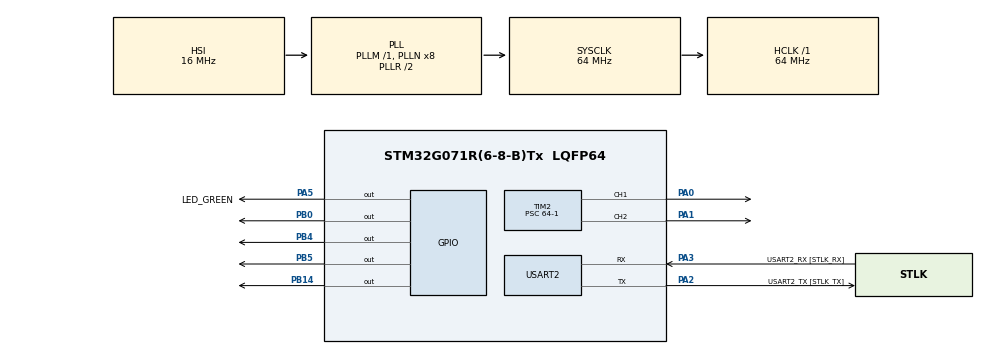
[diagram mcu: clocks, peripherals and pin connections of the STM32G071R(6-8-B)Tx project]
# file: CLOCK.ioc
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Mcu.Family=STM32G0
Mcu.Name=STM32G071R(6-8-B)Tx
Mcu.Package=LQFP64
PA0.Signal=S_TIM2_CH1_ETR
PA1.Signal=S_TIM2_CH2
PA13.GPIO_Label=TMS
PA13.Mode=Serial_Wire
PA13.Signal=SYS_SWDIO
PA14-BOOT0.GPIO_Label=TCK
PA14-BOOT0.Mode=Serial_Wire
PA14-BOOT0.Signal=SYS_SWCLK
PA2.GPIO_Label=USART2_TX [STLK_TX]
PA2.GPIO_PuPd=GPIO_PULLUP
PA2.Mode=Asynchronous
PA2.Signal=USART2_TX
PA3.GPIO_Label=USART2_RX [STLK_RX]
PA3.GPIO_PuPd=GPIO_PULLUP
PA3.Mode=Asynchronous
PA3.Signal=USART2_RX
PA5.GPIO_Label=LED_GREEN
PA5.GPIO_Speed=GPIO_SPEED_FREQ_HIGH
PA5.Signal=GPIO_Output
PB0.Signal=GPIO_Output
PB14.Signal=GPIO_Output
PB4.Signal=GPIO_Output
PB5.Signal=GPIO_Output
PC13.Mode=SYS_WakeUp1
PC13.Signal=SYS_WKUP2
PC14-OSC32_IN\ (PC14).Mode=LSE-External-Oscillator
PC14-OSC32_IN\ (PC14).Signal=RCC_OSC32_IN
PC15-OSC32_OUT\ (PC15).Mode=LSE-External-Oscillator
PC15-OSC32_OUT\ (PC15).Signal=RCC_OSC32_OUT
PF0-OSC_IN\ (PF0).GPIO_Label=MCO
PF0-OSC_IN\ (PF0).Mode=HSE-External-Oscillator
PF0-OSC_IN\ (PF0).Signal=RCC_OSC_IN
PF1-OSC_OUT\ (PF1).Mode=HSE-External-Oscillator
PF1-OSC_OUT\ (PF1).Signal=RCC_OSC_OUT
ProjectManager.HeapSize=0x200
ProjectManager.StackSize=0x400
ProjectManager.TargetToolchain=STM32CubeIDE
RCC.ADCFreq_Value=64000000
RCC.AHBFreq_Value=64000000
RCC.CortexFreq_Value=64000000
RCC.EXTERNAL_CLOCK_VALUE=12288000
RCC.HCLKFreq_Value=64000000
RCC.HSE_VALUE=8000000
RCC.HSI_VALUE=16000000
RCC.SYSCLKFreq_VALUE=64000000
RCC.SYSCLKSource=RCC_SYSCLKSOURCE_PLLCLK
RCC.VCOOutputFreq_Value=128000000
SH.S_TIM2_CH1_ETR.0=TIM2_CH1,PWM Generation1 CH1
SH.S_TIM2_CH2.0=TIM2_CH2,PWM Generation2 CH2
TIM2.AutoReloadPreload=TIM_AUTORELOAD_PRELOAD_ENABLE
TIM2.Channel-PWM\ Generation1\ CH1=TIM_CHANNEL_1
TIM2.Channel-PWM\ Generation2\ CH2=TIM_CHANNEL_2
TIM2.Period=100
TIM2.Prescaler=64-1
USART2.VirtualMode-Asynchronous=VM_ASYNC
VP_TIM2_VS_ClockSourceINT.Mode=Internal
board=NUCLEO-G071RB

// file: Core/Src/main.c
/* USER CODE BEGIN Header */
/**
  ******************************************************************************
  * @file           : main.c
  * @brief          : Main program body
  ******************************************************************************
  * @attention
  *
  * Copyright (c) 2023 STMicroelectronics.
  * All rights reserved.
  *
  * This software is licensed under terms that can be found in the LICENSE file
  * in the root directory of this software component.
  * If no LICENSE file comes with this software, it is provided AS-IS.
  *
  ******************************************************************************
  */
/* USER CODE END Header */
#include "main.h"

#define FORWARD_STATE HAL_GPIO_ReadPin(GPIOA, GPIO_PIN_9)
#define LEFT_STATE HAL_GPIO_ReadPin(GPIOC, GPIO_PIN_7)
#define RIGHT_STATE HAL_GPIO_ReadPin(GPIOA, GPIO_PIN_8)
#define BACKWARD_STATE HAL_GPIO_ReadPin(GPIOA, GPIO_PIN_7)

TIM_HandleTypeDef htim2;

UART_HandleTypeDef huart2;

void SystemClock_Config(void);
static void MX_GPIO_Init(void);
static void MX_USART2_UART_Init(void);
static void MX_TIM2_Init(void);

int main(void)
{
  /* USER CODE BEGIN 1 */
 //int32_t CH1_DC = 0;
  /* USER CODE END 1 */

  /* MCU Configuration--------------------------------------------------------*/

  /* Reset of all peripherals, Initializes the Flash interface and the Systick. */
  HAL_Init();

  /* Configure the system clock */
  SystemClock_Config();

  /* Initialize all configured peripherals */
  MX_GPIO_Init();
  MX_USART2_UART_Init();
  MX_TIM2_Init();
  /* USER CODE BEGIN 2 */
  HAL_TIM_PWM_Start(&htim2, TIM_CHANNEL_1);
  HAL_TIM_PWM_Start(&htim2, TIM_CHANNEL_2);
  void FORWARD_DIR(void)
    {
    	HAL_GPIO_WritePin(GPIOB, GPIO_PIN_0|GPIO_PIN_4,  GPIO_PIN_RESET);
    	HAL_GPIO_WritePin(GPIOB, GPIO_PIN_14|GPIO_PIN_5,  GPIO_PIN_SET);
    	TIM2->CCR1 = 70;
    	TIM2->CCR2 = 70;
    	// GIVE PWMA 100% AND PWMB 100%
    	}

  void BACKWARD_DIR(void)
	{
		HAL_GPIO_WritePin(GPIOB, GPIO_PIN_0|GPIO_PIN_4,  GPIO_PIN_SET);
		HAL_GPIO_WritePin(GPIOB, GPIO_PIN_14|GPIO_PIN_5,  GPIO_PIN_RESET);
		TIM2->CCR1 = 70;
		TIM2->CCR2 = 70;
		// GIVE PWMA 100% AND PWMB 100%
		}

  void LEFT_DIR(void)
    {
    	HAL_GPIO_WritePin(GPIOB, GPIO_PIN_8|GPIO_PIN_4,  GPIO_PIN_RESET);
    	HAL_GPIO_WritePin(GPIOB, GPIO_PIN_14|GPIO_PIN_5,  GPIO_PIN_SET);
    	TIM2->CCR1 = 10;
    	TIM2->CCR2 = 80;
    	// GIVE PWMA AND PWMB
    	}

  void RIGHT_DIR(void)
    {
    	HAL_GPIO_WritePin(GPIOB, GPIO_PIN_8|GPIO_PIN_4,  GPIO_PIN_RESET);
    	HAL_GPIO_WritePin(GPIOB, GPIO_PIN_14|GPIO_PIN_5,  GPIO_PIN_SET);
    	TIM2->CCR1 = 80;
    	TIM2->CCR2 = 10;
    	// GIVE PWMA AND PWMB
    	}

  void STOP(void)
      {
      	HAL_GPIO_WritePin(GPIOB, GPIO_PIN_8|GPIO_PIN_4,  GPIO_PIN_RESET);
      	HAL_GPIO_WritePin(GPIOB, GPIO_PIN_14|GPIO_PIN_5,  GPIO_PIN_RESET);
      	TIM2->CCR1 = 0;
      	TIM2->CCR2 = 0;
      	// GIVE PWMA AND PWMB
      	}

  /* USER CODE END 2 */

  /* Infinite loop */
  while (1)
  {
	  if(FORWARD_STATE == 1)
		  {
			  FORWARD_DIR();
		  }
	  if(LEFT_STATE == 1)
		  {
			  LEFT_DIR();
		  }
	  if(RIGHT_STATE == 1)
		  {
			  RIGHT_DIR();
		  }
	  if(BACKWARD_STATE == 1)
		  {
			  BACKWARD_DIR();
		  }
	  if(FORWARD_STATE == 0 && LEFT_STATE == 0 && RIGHT_STATE == 0 && BACKWARD_STATE == 0)
		  {
		      STOP();
		  }
  }
}

void SystemClock_Config(void)
{
  RCC_OscInitTypeDef RCC_OscInitStruct = {0};
  RCC_ClkInitTypeDef RCC_ClkInitStruct = {0};

  /** Configure the main internal regulator output voltage
  */
  HAL_PWREx_ControlVoltageScaling(PWR_REGULATOR_VOLTAGE_SCALE1);

  /** Initializes the RCC Oscillators according to the specified parameters
  * in the RCC_OscInitTypeDef structure.
  */
  RCC_OscInitStruct.OscillatorType = RCC_OSCILLATORTYPE_HSI;
  RCC_OscInitStruct.HSIState = RCC_HSI_ON;
  RCC_OscInitStruct.HSIDiv = RCC_HSI_DIV1;
  RCC_OscInitStruct.HSICalibrationValue = RCC_HSICALIBRATION_DEFAULT;
  RCC_OscInitStruct.PLL.PLLState = RCC_PLL_ON;
  RCC_OscInitStruct.PLL.PLLSource = RCC_PLLSOURCE_HSI;
  RCC_OscInitStruct.PLL.PLLM = RCC_PLLM_DIV1;
  RCC_OscInitStruct.PLL.PLLN = 8;
  RCC_OscInitStruct.PLL.PLLP = RCC_PLLP_DIV2;
  RCC_OscInitStruct.PLL.PLLQ = RCC_PLLQ_DIV2;
  RCC_OscInitStruct.PLL.PLLR = RCC_PLLR_DIV2;
  if (HAL_RCC_OscConfig(&RCC_OscInitStruct) != HAL_OK)
  {
    Error_Handler();
  }

  /** Initializes the CPU, AHB and APB buses clocks
  */
  RCC_ClkInitStruct.ClockType = RCC_CLOCKTYPE_HCLK|RCC_CLOCKTYPE_SYSCLK
                              |RCC_CLOCKTYPE_PCLK1;
  RCC_ClkInitStruct.SYSCLKSource = RCC_SYSCLKSOURCE_PLLCLK;
  RCC_ClkInitStruct.AHBCLKDivider = RCC_SYSCLK_DIV1;
  RCC_ClkInitStruct.APB1CLKDivider = RCC_HCLK_DIV1;

  if (HAL_RCC_ClockConfig(&RCC_ClkInitStruct, FLASH_LATENCY_2) != HAL_OK)
  {
    Error_Handler();
  }
}

static void MX_TIM2_Init(void)
{

  TIM_ClockConfigTypeDef sClockSourceConfig = {0};
  TIM_MasterConfigTypeDef sMasterConfig = {0};
  TIM_OC_InitTypeDef sConfigOC = {0};

  htim2.Instance = TIM2;
  htim2.Init.Prescaler = 64-1;
  htim2.Init.CounterMode = TIM_COUNTERMODE_UP;
  htim2.Init.Period = 100;
  htim2.Init.ClockDivision = TIM_CLOCKDIVISION_DIV1;
  htim2.Init.AutoReloadPreload = TIM_AUTORELOAD_PRELOAD_ENABLE;
  if (HAL_TIM_Base_Init(&htim2) != HAL_OK)
  {
    Error_Handler();
  }
  sClockSourceConfig.ClockSource = TIM_CLOCKSOURCE_INTERNAL;
  if (HAL_TIM_ConfigClockSource(&htim2, &sClockSourceConfig) != HAL_OK)
  {
    Error_Handler();
  }
  if (HAL_TIM_PWM_Init(&htim2) != HAL_OK)
  {
    Error_Handler();
  }
  sMasterConfig.MasterOutputTrigger = TIM_TRGO_RESET;
  sMasterConfig.MasterSlaveMode = TIM_MASTERSLAVEMODE_DISABLE;
  if (HAL_TIMEx_MasterConfigSynchronization(&htim2, &sMasterConfig) != HAL_OK)
  {
    Error_Handler();
  }
  sConfigOC.OCMode = TIM_OCMODE_PWM1;
  sConfigOC.Pulse = 0;
  sConfigOC.OCPolarity = TIM_OCPOLARITY_HIGH;
  sConfigOC.OCFastMode = TIM_OCFAST_DISABLE;
  if (HAL_TIM_PWM_ConfigChannel(&htim2, &sConfigOC, TIM_CHANNEL_1) != HAL_OK)
  {
    Error_Handler();
  }
  if (HAL_TIM_PWM_ConfigChannel(&htim2, &sConfigOC, TIM_CHANNEL_2) != HAL_OK)
  {
    Error_Handler();
  }
  HAL_TIM_MspPostInit(&htim2);

}

static void MX_USART2_UART_Init(void)
{

  huart2.Instance = USART2;
  huart2.Init.BaudRate = 115200;
  huart2.Init.WordLength = UART_WORDLENGTH_8B;
  huart2.Init.StopBits = UART_STOPBITS_1;
  huart2.Init.Parity = UART_PARITY_NONE;
  huart2.Init.Mode = UART_MODE_TX_RX;
  huart2.Init.HwFlowCtl = UART_HWCONTROL_NONE;
  huart2.Init.OverSampling = UART_OVERSAMPLING_16;
  huart2.Init.OneBitSampling = UART_ONE_BIT_SAMPLE_DISABLE;
  huart2.Init.ClockPrescaler = UART_PRESCALER_DIV1;
  huart2.AdvancedInit.AdvFeatureInit = UART_ADVFEATURE_NO_INIT;
  if (HAL_UART_Init(&huart2) != HAL_OK)
  {
    Error_Handler();
  }
  if (HAL_UARTEx_SetTxFifoThreshold(&huart2, UART_TXFIFO_THRESHOLD_1_8) != HAL_OK)
  {
    Error_Handler();
  }
  if (HAL_UARTEx_SetRxFifoThreshold(&huart2, UART_RXFIFO_THRESHOLD_1_8) != HAL_OK)
  {
    Error_Handler();
  }
  if (HAL_UARTEx_DisableFifoMode(&huart2) != HAL_OK)
  {
    Error_Handler();
  }

}

static void MX_GPIO_Init(void)
{
  GPIO_InitTypeDef GPIO_InitStruct = {0};

  /* GPIO Ports Clock Enable */
  __HAL_RCC_GPIOC_CLK_ENABLE();
  __HAL_RCC_GPIOF_CLK_ENABLE();
  __HAL_RCC_GPIOA_CLK_ENABLE();
  __HAL_RCC_GPIOB_CLK_ENABLE();

  /*Configure GPIO pin Output Level */
  HAL_GPIO_WritePin(LED_GREEN_GPIO_Port, LED_GREEN_Pin, GPIO_PIN_RESET);

  /*Configure GPIO pin Output Level */
  HAL_GPIO_WritePin(GPIOB, GPIO_PIN_0|GPIO_PIN_14|GPIO_PIN_4|GPIO_PIN_5, GPIO_PIN_RESET);

  /*Configure GPIO pin : LED_GREEN_Pin */
  GPIO_InitStruct.Pin = LED_GREEN_Pin;
  GPIO_InitStruct.Mode = GPIO_MODE_OUTPUT_PP;
  GPIO_InitStruct.Pull = GPIO_NOPULL;
  GPIO_InitStruct.Speed = GPIO_SPEED_FREQ_HIGH;
  HAL_GPIO_Init(LED_GREEN_GPIO_Port, &GPIO_InitStruct);

  /*Configure GPIO pins : PA7 PA8 PA9 */
  GPIO_InitStruct.Pin = GPIO_PIN_7|GPIO_PIN_8|GPIO_PIN_9;
  GPIO_InitStruct.Mode = GPIO_MODE_INPUT;
  GPIO_InitStruct.Pull = GPIO_NOPULL;
  HAL_GPIO_Init(GPIOA, &GPIO_InitStruct);

  /*Configure GPIO pins : PB0 PB14 PB4 PB5 */
  GPIO_InitStruct.Pin = GPIO_PIN_0|GPIO_PIN_14|GPIO_PIN_4|GPIO_PIN_5;
  GPIO_InitStruct.Mode = GPIO_MODE_OUTPUT_PP;
  GPIO_InitStruct.Pull = GPIO_NOPULL;
  GPIO_InitStruct.Speed = GPIO_SPEED_FREQ_LOW;
  HAL_GPIO_Init(GPIOB, &GPIO_InitStruct);

  /*Configure GPIO pin : PC7 */
  GPIO_InitStruct.Pin = GPIO_PIN_7;
  GPIO_InitStruct.Mode = GPIO_MODE_INPUT;
  GPIO_InitStruct.Pull = GPIO_NOPULL;
  HAL_GPIO_Init(GPIOC, &GPIO_InitStruct);

}

void Error_Handler(void)
{
  __disable_irq();
  while (1)
  {
  }
}
